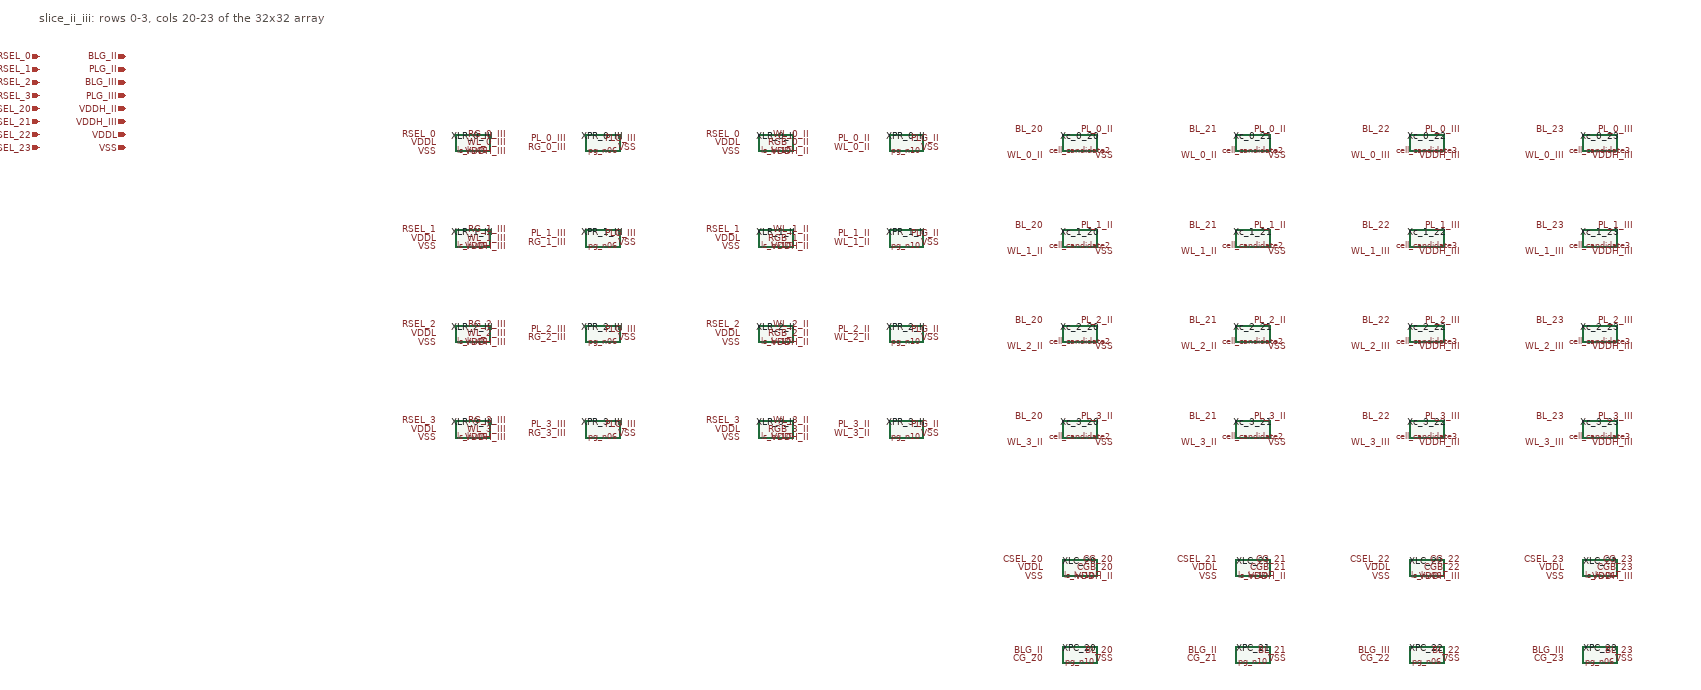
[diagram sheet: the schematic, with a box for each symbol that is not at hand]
v {xschem version=3.4.7 file_version=1.2

* gf180-antifuse: slice_ii_iii - GENERATED by design/gen_array.py. Do not hand-edit;
* edit the generator and rerun design/regen-netlists.sh.
*
* Rows 0..3, columns 20..23 of the N=32 array (absolute coordinates),
* with the row/column local high-voltage addressing stage of
* spec/architecture.md 1.1 (level shifter -> HV pass-gate).
*
* Per-cell wcap/lcap/wacc/lacc and candidate type follow the region map in
* spec/split-axis-plan.md; design/check-array.py fails if they drift.
*
* Nets: BL_<c> column bit line; WL_<r>_<band> / PL_<r>_<band> word / plate line
* of one row segment; BLG_<band> / PLG_<band> per-band global bus the (out of
* scope) program / read legs attach to; CSEL_<c> / RSEL_<r> single-ended
* one-hot selects from the digital partition; VDDH_<band> level-shifter rail.
* Candidate 3's word line is active-low (PMOS access) and its cell VB is the
* band's VDDH rail (n-well tie at the most positive potential).
*
* PROVISIONAL CONVENTIONS (not ratified) - open items for the operator,
* numbered (a)-(e) with alternatives and consequences in design/README.md
* ("PROVISIONAL resolutions - open items for the operator"):
*   (a) 'min' geometry = the cell subckt placeholder defaults; '2x' = width x2.
*   (b) interleave phase: cap (r+c') mod 2, access (r//2+c'//2) mod 2,
*       band-relative column c'.
*   (c) band axis = column; row stage per (row, band); per-band BLG/PLG/VDDH.
*   (d) Region II level shifters/pass-gates use the 10 V asymmetric pair.
*   (e) NMOS pass-gate gate rail = VDDH (passes at most VDDH - Vth).
}
G {}
K {}
V {}
S {}
E {}
C {cell_candidate2.sym} 400 300 0 0 {name=Xc_0_20
wcap=2e-6
lcap=1e-6
wacc=25u
lacc=0.60u
m=1}
C {devices/lab_pin.sym} 320 270 0 0 {name=l1 sig_type=std_logic lab=BL_20}
C {devices/lab_pin.sym} 320 330 0 0 {name=l2 sig_type=std_logic lab=WL_0_II}
C {devices/lab_pin.sym} 480 270 0 0 {name=l3 sig_type=std_logic lab=PL_0_II}
C {devices/lab_pin.sym} 480 330 0 0 {name=l4 sig_type=std_logic lab=VSS}
C {cell_candidate2.sym} 800 300 0 0 {name=Xc_0_21
wcap=1e-6
lcap=1e-6
wacc=50u
lacc=0.60u
m=1}
C {devices/lab_pin.sym} 720 270 0 0 {name=l5 sig_type=std_logic lab=BL_21}
C {devices/lab_pin.sym} 720 330 0 0 {name=l6 sig_type=std_logic lab=WL_0_II}
C {devices/lab_pin.sym} 880 270 0 0 {name=l7 sig_type=std_logic lab=PL_0_II}
C {devices/lab_pin.sym} 880 330 0 0 {name=l8 sig_type=std_logic lab=VSS}
C {cell_candidate3.sym} 1200 300 0 0 {name=Xc_0_22
wcap=1e-6
lcap=1e-6
wacc=0.30u
lacc=0.55u
m=1}
C {devices/lab_pin.sym} 1120 270 0 0 {name=l9 sig_type=std_logic lab=BL_22}
C {devices/lab_pin.sym} 1120 330 0 0 {name=l10 sig_type=std_logic lab=WL_0_III}
C {devices/lab_pin.sym} 1280 270 0 0 {name=l11 sig_type=std_logic lab=PL_0_III}
C {devices/lab_pin.sym} 1280 330 0 0 {name=l12 sig_type=std_logic lab=VDDH_III}
C {cell_candidate3.sym} 1600 300 0 0 {name=Xc_0_23
wcap=2e-6
lcap=1e-6
wacc=0.30u
lacc=0.55u
m=1}
C {devices/lab_pin.sym} 1520 270 0 0 {name=l13 sig_type=std_logic lab=BL_23}
C {devices/lab_pin.sym} 1520 330 0 0 {name=l14 sig_type=std_logic lab=WL_0_III}
C {devices/lab_pin.sym} 1680 270 0 0 {name=l15 sig_type=std_logic lab=PL_0_III}
C {devices/lab_pin.sym} 1680 330 0 0 {name=l16 sig_type=std_logic lab=VDDH_III}
C {cell_candidate2.sym} 400 520 0 0 {name=Xc_1_20
wcap=1e-6
lcap=1e-6
wacc=25u
lacc=0.60u
m=1}
C {devices/lab_pin.sym} 320 490 0 0 {name=l17 sig_type=std_logic lab=BL_20}
C {devices/lab_pin.sym} 320 550 0 0 {name=l18 sig_type=std_logic lab=WL_1_II}
C {devices/lab_pin.sym} 480 490 0 0 {name=l19 sig_type=std_logic lab=PL_1_II}
C {devices/lab_pin.sym} 480 550 0 0 {name=l20 sig_type=std_logic lab=VSS}
C {cell_candidate2.sym} 800 520 0 0 {name=Xc_1_21
wcap=2e-6
lcap=1e-6
wacc=50u
lacc=0.60u
m=1}
C {devices/lab_pin.sym} 720 490 0 0 {name=l21 sig_type=std_logic lab=BL_21}
C {devices/lab_pin.sym} 720 550 0 0 {name=l22 sig_type=std_logic lab=WL_1_II}
C {devices/lab_pin.sym} 880 490 0 0 {name=l23 sig_type=std_logic lab=PL_1_II}
C {devices/lab_pin.sym} 880 550 0 0 {name=l24 sig_type=std_logic lab=VSS}
C {cell_candidate3.sym} 1200 520 0 0 {name=Xc_1_22
wcap=2e-6
lcap=1e-6
wacc=0.30u
lacc=0.55u
m=1}
C {devices/lab_pin.sym} 1120 490 0 0 {name=l25 sig_type=std_logic lab=BL_22}
C {devices/lab_pin.sym} 1120 550 0 0 {name=l26 sig_type=std_logic lab=WL_1_III}
C {devices/lab_pin.sym} 1280 490 0 0 {name=l27 sig_type=std_logic lab=PL_1_III}
C {devices/lab_pin.sym} 1280 550 0 0 {name=l28 sig_type=std_logic lab=VDDH_III}
C {cell_candidate3.sym} 1600 520 0 0 {name=Xc_1_23
wcap=1e-6
lcap=1e-6
wacc=0.30u
lacc=0.55u
m=1}
C {devices/lab_pin.sym} 1520 490 0 0 {name=l29 sig_type=std_logic lab=BL_23}
C {devices/lab_pin.sym} 1520 550 0 0 {name=l30 sig_type=std_logic lab=WL_1_III}
C {devices/lab_pin.sym} 1680 490 0 0 {name=l31 sig_type=std_logic lab=PL_1_III}
C {devices/lab_pin.sym} 1680 550 0 0 {name=l32 sig_type=std_logic lab=VDDH_III}
C {cell_candidate2.sym} 400 740 0 0 {name=Xc_2_20
wcap=2e-6
lcap=1e-6
wacc=50u
lacc=0.60u
m=1}
C {devices/lab_pin.sym} 320 710 0 0 {name=l33 sig_type=std_logic lab=BL_20}
C {devices/lab_pin.sym} 320 770 0 0 {name=l34 sig_type=std_logic lab=WL_2_II}
C {devices/lab_pin.sym} 480 710 0 0 {name=l35 sig_type=std_logic lab=PL_2_II}
C {devices/lab_pin.sym} 480 770 0 0 {name=l36 sig_type=std_logic lab=VSS}
C {cell_candidate2.sym} 800 740 0 0 {name=Xc_2_21
wcap=1e-6
lcap=1e-6
wacc=25u
lacc=0.60u
m=1}
C {devices/lab_pin.sym} 720 710 0 0 {name=l37 sig_type=std_logic lab=BL_21}
C {devices/lab_pin.sym} 720 770 0 0 {name=l38 sig_type=std_logic lab=WL_2_II}
C {devices/lab_pin.sym} 880 710 0 0 {name=l39 sig_type=std_logic lab=PL_2_II}
C {devices/lab_pin.sym} 880 770 0 0 {name=l40 sig_type=std_logic lab=VSS}
C {cell_candidate3.sym} 1200 740 0 0 {name=Xc_2_22
wcap=1e-6
lcap=1e-6
wacc=0.6u
lacc=0.55u
m=1}
C {devices/lab_pin.sym} 1120 710 0 0 {name=l41 sig_type=std_logic lab=BL_22}
C {devices/lab_pin.sym} 1120 770 0 0 {name=l42 sig_type=std_logic lab=WL_2_III}
C {devices/lab_pin.sym} 1280 710 0 0 {name=l43 sig_type=std_logic lab=PL_2_III}
C {devices/lab_pin.sym} 1280 770 0 0 {name=l44 sig_type=std_logic lab=VDDH_III}
C {cell_candidate3.sym} 1600 740 0 0 {name=Xc_2_23
wcap=2e-6
lcap=1e-6
wacc=0.6u
lacc=0.55u
m=1}
C {devices/lab_pin.sym} 1520 710 0 0 {name=l45 sig_type=std_logic lab=BL_23}
C {devices/lab_pin.sym} 1520 770 0 0 {name=l46 sig_type=std_logic lab=WL_2_III}
C {devices/lab_pin.sym} 1680 710 0 0 {name=l47 sig_type=std_logic lab=PL_2_III}
C {devices/lab_pin.sym} 1680 770 0 0 {name=l48 sig_type=std_logic lab=VDDH_III}
C {cell_candidate2.sym} 400 960 0 0 {name=Xc_3_20
wcap=1e-6
lcap=1e-6
wacc=50u
lacc=0.60u
m=1}
C {devices/lab_pin.sym} 320 930 0 0 {name=l49 sig_type=std_logic lab=BL_20}
C {devices/lab_pin.sym} 320 990 0 0 {name=l50 sig_type=std_logic lab=WL_3_II}
C {devices/lab_pin.sym} 480 930 0 0 {name=l51 sig_type=std_logic lab=PL_3_II}
C {devices/lab_pin.sym} 480 990 0 0 {name=l52 sig_type=std_logic lab=VSS}
C {cell_candidate2.sym} 800 960 0 0 {name=Xc_3_21
wcap=2e-6
lcap=1e-6
wacc=25u
lacc=0.60u
m=1}
C {devices/lab_pin.sym} 720 930 0 0 {name=l53 sig_type=std_logic lab=BL_21}
C {devices/lab_pin.sym} 720 990 0 0 {name=l54 sig_type=std_logic lab=WL_3_II}
C {devices/lab_pin.sym} 880 930 0 0 {name=l55 sig_type=std_logic lab=PL_3_II}
C {devices/lab_pin.sym} 880 990 0 0 {name=l56 sig_type=std_logic lab=VSS}
C {cell_candidate3.sym} 1200 960 0 0 {name=Xc_3_22
wcap=2e-6
lcap=1e-6
wacc=0.6u
lacc=0.55u
m=1}
C {devices/lab_pin.sym} 1120 930 0 0 {name=l57 sig_type=std_logic lab=BL_22}
C {devices/lab_pin.sym} 1120 990 0 0 {name=l58 sig_type=std_logic lab=WL_3_III}
C {devices/lab_pin.sym} 1280 930 0 0 {name=l59 sig_type=std_logic lab=PL_3_III}
C {devices/lab_pin.sym} 1280 990 0 0 {name=l60 sig_type=std_logic lab=VDDH_III}
C {cell_candidate3.sym} 1600 960 0 0 {name=Xc_3_23
wcap=1e-6
lcap=1e-6
wacc=0.6u
lacc=0.55u
m=1}
C {devices/lab_pin.sym} 1520 930 0 0 {name=l61 sig_type=std_logic lab=BL_23}
C {devices/lab_pin.sym} 1520 990 0 0 {name=l62 sig_type=std_logic lab=WL_3_III}
C {devices/lab_pin.sym} 1680 930 0 0 {name=l63 sig_type=std_logic lab=PL_3_III}
C {devices/lab_pin.sym} 1680 990 0 0 {name=l64 sig_type=std_logic lab=VDDH_III}
C {ls_hv10.sym} 400 1280 0 0 {name=XLC_20}
C {devices/lab_pin.sym} 320 1260 0 0 {name=l65 sig_type=std_logic lab=CSEL_20}
C {devices/lab_pin.sym} 320 1280 0 0 {name=l66 sig_type=std_logic lab=VDDL}
C {devices/lab_pin.sym} 320 1300 0 0 {name=l67 sig_type=std_logic lab=VSS}
C {devices/lab_pin.sym} 480 1260 0 0 {name=l68 sig_type=std_logic lab=CG_20}
C {devices/lab_pin.sym} 480 1280 0 0 {name=l69 sig_type=std_logic lab=CGB_20}
C {devices/lab_pin.sym} 480 1300 0 0 {name=l70 sig_type=std_logic lab=VDDH_II}
C {pg_n10.sym} 400 1480 0 0 {name=XPC_20}
C {devices/lab_pin.sym} 320 1470 0 0 {name=l71 sig_type=std_logic lab=BLG_II}
C {devices/lab_pin.sym} 320 1490 0 0 {name=l72 sig_type=std_logic lab=CG_20}
C {devices/lab_pin.sym} 480 1470 0 0 {name=l73 sig_type=std_logic lab=BL_20}
C {devices/lab_pin.sym} 480 1490 0 0 {name=l74 sig_type=std_logic lab=VSS}
C {ls_hv10.sym} 800 1280 0 0 {name=XLC_21}
C {devices/lab_pin.sym} 720 1260 0 0 {name=l75 sig_type=std_logic lab=CSEL_21}
C {devices/lab_pin.sym} 720 1280 0 0 {name=l76 sig_type=std_logic lab=VDDL}
C {devices/lab_pin.sym} 720 1300 0 0 {name=l77 sig_type=std_logic lab=VSS}
C {devices/lab_pin.sym} 880 1260 0 0 {name=l78 sig_type=std_logic lab=CG_21}
C {devices/lab_pin.sym} 880 1280 0 0 {name=l79 sig_type=std_logic lab=CGB_21}
C {devices/lab_pin.sym} 880 1300 0 0 {name=l80 sig_type=std_logic lab=VDDH_II}
C {pg_n10.sym} 800 1480 0 0 {name=XPC_21}
C {devices/lab_pin.sym} 720 1470 0 0 {name=l81 sig_type=std_logic lab=BLG_II}
C {devices/lab_pin.sym} 720 1490 0 0 {name=l82 sig_type=std_logic lab=CG_21}
C {devices/lab_pin.sym} 880 1470 0 0 {name=l83 sig_type=std_logic lab=BL_21}
C {devices/lab_pin.sym} 880 1490 0 0 {name=l84 sig_type=std_logic lab=VSS}
C {ls_hv06.sym} 1200 1280 0 0 {name=XLC_22}
C {devices/lab_pin.sym} 1120 1260 0 0 {name=l85 sig_type=std_logic lab=CSEL_22}
C {devices/lab_pin.sym} 1120 1280 0 0 {name=l86 sig_type=std_logic lab=VDDL}
C {devices/lab_pin.sym} 1120 1300 0 0 {name=l87 sig_type=std_logic lab=VSS}
C {devices/lab_pin.sym} 1280 1260 0 0 {name=l88 sig_type=std_logic lab=CG_22}
C {devices/lab_pin.sym} 1280 1280 0 0 {name=l89 sig_type=std_logic lab=CGB_22}
C {devices/lab_pin.sym} 1280 1300 0 0 {name=l90 sig_type=std_logic lab=VDDH_III}
C {pg_n06.sym} 1200 1480 0 0 {name=XPC_22}
C {devices/lab_pin.sym} 1120 1470 0 0 {name=l91 sig_type=std_logic lab=BLG_III}
C {devices/lab_pin.sym} 1120 1490 0 0 {name=l92 sig_type=std_logic lab=CG_22}
C {devices/lab_pin.sym} 1280 1470 0 0 {name=l93 sig_type=std_logic lab=BL_22}
C {devices/lab_pin.sym} 1280 1490 0 0 {name=l94 sig_type=std_logic lab=VSS}
C {ls_hv06.sym} 1600 1280 0 0 {name=XLC_23}
C {devices/lab_pin.sym} 1520 1260 0 0 {name=l95 sig_type=std_logic lab=CSEL_23}
C {devices/lab_pin.sym} 1520 1280 0 0 {name=l96 sig_type=std_logic lab=VDDL}
C {devices/lab_pin.sym} 1520 1300 0 0 {name=l97 sig_type=std_logic lab=VSS}
C {devices/lab_pin.sym} 1680 1260 0 0 {name=l98 sig_type=std_logic lab=CG_23}
C {devices/lab_pin.sym} 1680 1280 0 0 {name=l99 sig_type=std_logic lab=CGB_23}
C {devices/lab_pin.sym} 1680 1300 0 0 {name=l100 sig_type=std_logic lab=VDDH_III}
C {pg_n06.sym} 1600 1480 0 0 {name=XPC_23}
C {devices/lab_pin.sym} 1520 1470 0 0 {name=l101 sig_type=std_logic lab=BLG_III}
C {devices/lab_pin.sym} 1520 1490 0 0 {name=l102 sig_type=std_logic lab=CG_23}
C {devices/lab_pin.sym} 1680 1470 0 0 {name=l103 sig_type=std_logic lab=BL_23}
C {devices/lab_pin.sym} 1680 1490 0 0 {name=l104 sig_type=std_logic lab=VSS}
C {ls_hv10.sym} -300 300 0 0 {name=XLR_0_II}
C {devices/lab_pin.sym} -380 280 0 0 {name=l105 sig_type=std_logic lab=RSEL_0}
C {devices/lab_pin.sym} -380 300 0 0 {name=l106 sig_type=std_logic lab=VDDL}
C {devices/lab_pin.sym} -380 320 0 0 {name=l107 sig_type=std_logic lab=VSS}
C {devices/lab_pin.sym} -220 280 0 0 {name=l108 sig_type=std_logic lab=WL_0_II}
C {devices/lab_pin.sym} -220 300 0 0 {name=l109 sig_type=std_logic lab=RGB_0_II}
C {devices/lab_pin.sym} -220 320 0 0 {name=l110 sig_type=std_logic lab=VDDH_II}
C {pg_n10.sym} 0 300 0 0 {name=XPR_0_II}
C {devices/lab_pin.sym} -80 290 0 0 {name=l111 sig_type=std_logic lab=PL_0_II}
C {devices/lab_pin.sym} -80 310 0 0 {name=l112 sig_type=std_logic lab=WL_0_II}
C {devices/lab_pin.sym} 80 290 0 0 {name=l113 sig_type=std_logic lab=PLG_II}
C {devices/lab_pin.sym} 80 310 0 0 {name=l114 sig_type=std_logic lab=VSS}
C {ls_hv10.sym} -300 520 0 0 {name=XLR_1_II}
C {devices/lab_pin.sym} -380 500 0 0 {name=l115 sig_type=std_logic lab=RSEL_1}
C {devices/lab_pin.sym} -380 520 0 0 {name=l116 sig_type=std_logic lab=VDDL}
C {devices/lab_pin.sym} -380 540 0 0 {name=l117 sig_type=std_logic lab=VSS}
C {devices/lab_pin.sym} -220 500 0 0 {name=l118 sig_type=std_logic lab=WL_1_II}
C {devices/lab_pin.sym} -220 520 0 0 {name=l119 sig_type=std_logic lab=RGB_1_II}
C {devices/lab_pin.sym} -220 540 0 0 {name=l120 sig_type=std_logic lab=VDDH_II}
C {pg_n10.sym} 0 520 0 0 {name=XPR_1_II}
C {devices/lab_pin.sym} -80 510 0 0 {name=l121 sig_type=std_logic lab=PL_1_II}
C {devices/lab_pin.sym} -80 530 0 0 {name=l122 sig_type=std_logic lab=WL_1_II}
C {devices/lab_pin.sym} 80 510 0 0 {name=l123 sig_type=std_logic lab=PLG_II}
C {devices/lab_pin.sym} 80 530 0 0 {name=l124 sig_type=std_logic lab=VSS}
C {ls_hv10.sym} -300 740 0 0 {name=XLR_2_II}
C {devices/lab_pin.sym} -380 720 0 0 {name=l125 sig_type=std_logic lab=RSEL_2}
C {devices/lab_pin.sym} -380 740 0 0 {name=l126 sig_type=std_logic lab=VDDL}
C {devices/lab_pin.sym} -380 760 0 0 {name=l127 sig_type=std_logic lab=VSS}
C {devices/lab_pin.sym} -220 720 0 0 {name=l128 sig_type=std_logic lab=WL_2_II}
C {devices/lab_pin.sym} -220 740 0 0 {name=l129 sig_type=std_logic lab=RGB_2_II}
C {devices/lab_pin.sym} -220 760 0 0 {name=l130 sig_type=std_logic lab=VDDH_II}
C {pg_n10.sym} 0 740 0 0 {name=XPR_2_II}
C {devices/lab_pin.sym} -80 730 0 0 {name=l131 sig_type=std_logic lab=PL_2_II}
C {devices/lab_pin.sym} -80 750 0 0 {name=l132 sig_type=std_logic lab=WL_2_II}
C {devices/lab_pin.sym} 80 730 0 0 {name=l133 sig_type=std_logic lab=PLG_II}
C {devices/lab_pin.sym} 80 750 0 0 {name=l134 sig_type=std_logic lab=VSS}
C {ls_hv10.sym} -300 960 0 0 {name=XLR_3_II}
C {devices/lab_pin.sym} -380 940 0 0 {name=l135 sig_type=std_logic lab=RSEL_3}
C {devices/lab_pin.sym} -380 960 0 0 {name=l136 sig_type=std_logic lab=VDDL}
C {devices/lab_pin.sym} -380 980 0 0 {name=l137 sig_type=std_logic lab=VSS}
C {devices/lab_pin.sym} -220 940 0 0 {name=l138 sig_type=std_logic lab=WL_3_II}
C {devices/lab_pin.sym} -220 960 0 0 {name=l139 sig_type=std_logic lab=RGB_3_II}
C {devices/lab_pin.sym} -220 980 0 0 {name=l140 sig_type=std_logic lab=VDDH_II}
C {pg_n10.sym} 0 960 0 0 {name=XPR_3_II}
C {devices/lab_pin.sym} -80 950 0 0 {name=l141 sig_type=std_logic lab=PL_3_II}
C {devices/lab_pin.sym} -80 970 0 0 {name=l142 sig_type=std_logic lab=WL_3_II}
C {devices/lab_pin.sym} 80 950 0 0 {name=l143 sig_type=std_logic lab=PLG_II}
C {devices/lab_pin.sym} 80 970 0 0 {name=l144 sig_type=std_logic lab=VSS}
C {ls_hv06.sym} -1000 300 0 0 {name=XLR_0_III}
C {devices/lab_pin.sym} -1080 280 0 0 {name=l145 sig_type=std_logic lab=RSEL_0}
C {devices/lab_pin.sym} -1080 300 0 0 {name=l146 sig_type=std_logic lab=VDDL}
C {devices/lab_pin.sym} -1080 320 0 0 {name=l147 sig_type=std_logic lab=VSS}
C {devices/lab_pin.sym} -920 280 0 0 {name=l148 sig_type=std_logic lab=RG_0_III}
C {devices/lab_pin.sym} -920 300 0 0 {name=l149 sig_type=std_logic lab=WL_0_III}
C {devices/lab_pin.sym} -920 320 0 0 {name=l150 sig_type=std_logic lab=VDDH_III}
C {pg_n06.sym} -700 300 0 0 {name=XPR_0_III}
C {devices/lab_pin.sym} -780 290 0 0 {name=l151 sig_type=std_logic lab=PL_0_III}
C {devices/lab_pin.sym} -780 310 0 0 {name=l152 sig_type=std_logic lab=RG_0_III}
C {devices/lab_pin.sym} -620 290 0 0 {name=l153 sig_type=std_logic lab=PLG_III}
C {devices/lab_pin.sym} -620 310 0 0 {name=l154 sig_type=std_logic lab=VSS}
C {ls_hv06.sym} -1000 520 0 0 {name=XLR_1_III}
C {devices/lab_pin.sym} -1080 500 0 0 {name=l155 sig_type=std_logic lab=RSEL_1}
C {devices/lab_pin.sym} -1080 520 0 0 {name=l156 sig_type=std_logic lab=VDDL}
C {devices/lab_pin.sym} -1080 540 0 0 {name=l157 sig_type=std_logic lab=VSS}
C {devices/lab_pin.sym} -920 500 0 0 {name=l158 sig_type=std_logic lab=RG_1_III}
C {devices/lab_pin.sym} -920 520 0 0 {name=l159 sig_type=std_logic lab=WL_1_III}
C {devices/lab_pin.sym} -920 540 0 0 {name=l160 sig_type=std_logic lab=VDDH_III}
C {pg_n06.sym} -700 520 0 0 {name=XPR_1_III}
C {devices/lab_pin.sym} -780 510 0 0 {name=l161 sig_type=std_logic lab=PL_1_III}
C {devices/lab_pin.sym} -780 530 0 0 {name=l162 sig_type=std_logic lab=RG_1_III}
C {devices/lab_pin.sym} -620 510 0 0 {name=l163 sig_type=std_logic lab=PLG_III}
C {devices/lab_pin.sym} -620 530 0 0 {name=l164 sig_type=std_logic lab=VSS}
C {ls_hv06.sym} -1000 740 0 0 {name=XLR_2_III}
C {devices/lab_pin.sym} -1080 720 0 0 {name=l165 sig_type=std_logic lab=RSEL_2}
C {devices/lab_pin.sym} -1080 740 0 0 {name=l166 sig_type=std_logic lab=VDDL}
C {devices/lab_pin.sym} -1080 760 0 0 {name=l167 sig_type=std_logic lab=VSS}
C {devices/lab_pin.sym} -920 720 0 0 {name=l168 sig_type=std_logic lab=RG_2_III}
C {devices/lab_pin.sym} -920 740 0 0 {name=l169 sig_type=std_logic lab=WL_2_III}
C {devices/lab_pin.sym} -920 760 0 0 {name=l170 sig_type=std_logic lab=VDDH_III}
C {pg_n06.sym} -700 740 0 0 {name=XPR_2_III}
C {devices/lab_pin.sym} -780 730 0 0 {name=l171 sig_type=std_logic lab=PL_2_III}
C {devices/lab_pin.sym} -780 750 0 0 {name=l172 sig_type=std_logic lab=RG_2_III}
C {devices/lab_pin.sym} -620 730 0 0 {name=l173 sig_type=std_logic lab=PLG_III}
C {devices/lab_pin.sym} -620 750 0 0 {name=l174 sig_type=std_logic lab=VSS}
C {ls_hv06.sym} -1000 960 0 0 {name=XLR_3_III}
C {devices/lab_pin.sym} -1080 940 0 0 {name=l175 sig_type=std_logic lab=RSEL_3}
C {devices/lab_pin.sym} -1080 960 0 0 {name=l176 sig_type=std_logic lab=VDDL}
C {devices/lab_pin.sym} -1080 980 0 0 {name=l177 sig_type=std_logic lab=VSS}
C {devices/lab_pin.sym} -920 940 0 0 {name=l178 sig_type=std_logic lab=RG_3_III}
C {devices/lab_pin.sym} -920 960 0 0 {name=l179 sig_type=std_logic lab=WL_3_III}
C {devices/lab_pin.sym} -920 980 0 0 {name=l180 sig_type=std_logic lab=VDDH_III}
C {pg_n06.sym} -700 960 0 0 {name=XPR_3_III}
C {devices/lab_pin.sym} -780 950 0 0 {name=l181 sig_type=std_logic lab=PL_3_III}
C {devices/lab_pin.sym} -780 970 0 0 {name=l182 sig_type=std_logic lab=RG_3_III}
C {devices/lab_pin.sym} -620 950 0 0 {name=l183 sig_type=std_logic lab=PLG_III}
C {devices/lab_pin.sym} -620 970 0 0 {name=l184 sig_type=std_logic lab=VSS}
C {devices/ipin.sym} -2000 100 0 0 {name=p185 lab=RSEL_0}
C {devices/ipin.sym} -2000 130 0 0 {name=p186 lab=RSEL_1}
C {devices/ipin.sym} -2000 160 0 0 {name=p187 lab=RSEL_2}
C {devices/ipin.sym} -2000 190 0 0 {name=p188 lab=RSEL_3}
C {devices/ipin.sym} -2000 220 0 0 {name=p189 lab=CSEL_20}
C {devices/ipin.sym} -2000 250 0 0 {name=p190 lab=CSEL_21}
C {devices/ipin.sym} -2000 280 0 0 {name=p191 lab=CSEL_22}
C {devices/ipin.sym} -2000 310 0 0 {name=p192 lab=CSEL_23}
C {devices/iopin.sym} -1800 100 0 0 {name=p193 lab=BLG_II}
C {devices/iopin.sym} -1800 130 0 0 {name=p194 lab=PLG_II}
C {devices/iopin.sym} -1800 160 0 0 {name=p195 lab=BLG_III}
C {devices/iopin.sym} -1800 190 0 0 {name=p196 lab=PLG_III}
C {devices/ipin.sym} -1800 220 0 0 {name=p197 lab=VDDH_II}
C {devices/ipin.sym} -1800 250 0 0 {name=p198 lab=VDDH_III}
C {devices/ipin.sym} -1800 280 0 0 {name=p199 lab=VDDL}
C {devices/ipin.sym} -1800 310 0 0 {name=p200 lab=VSS}
T {slice_ii_iii: rows 0-3, cols 20-23 of the 32x32 array} -2000 0 0 0 0.8 0.8 {}
